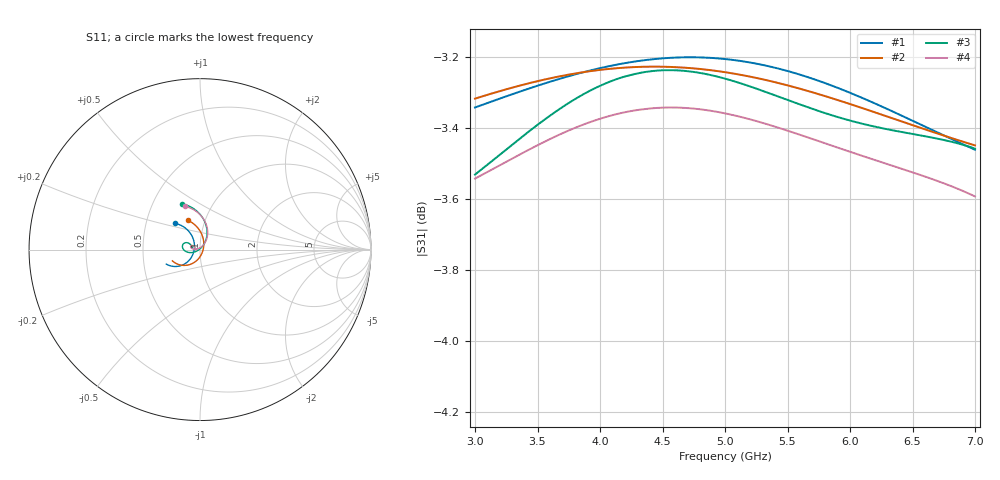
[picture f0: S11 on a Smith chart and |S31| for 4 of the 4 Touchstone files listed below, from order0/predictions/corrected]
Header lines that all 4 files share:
! |S21|, |S31| (and S12, S13) scaled, phases kept; 50 ohm, e^(+jwt)
# GHz S RI R 50
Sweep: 3 GHz to 7 GHz
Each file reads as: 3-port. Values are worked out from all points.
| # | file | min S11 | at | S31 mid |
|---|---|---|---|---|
| 1 | d1-m-eq-em528-fine-loss-corrected.s3p | -29.5 dB | 4.95 GHz | -3.2 dB at 5 GHz |
| 2 | d1-m-nom-fine-loss-corrected.s3p | -34.9 dB | 4.825 GHz | -3.2 dB at 5 GHz |
| 3 | d2-star-sched-w-eq-em528-fine-loss-corrected.s3p | -50.0 dB | 4.775 GHz | -3.3 dB at 5 GHz |
| 4 | d2-star-sched-w-nom-finer-loss-corrected.s3p | -40.7 dB | 5.1 GHz | -3.4 dB at 5 GHz |
